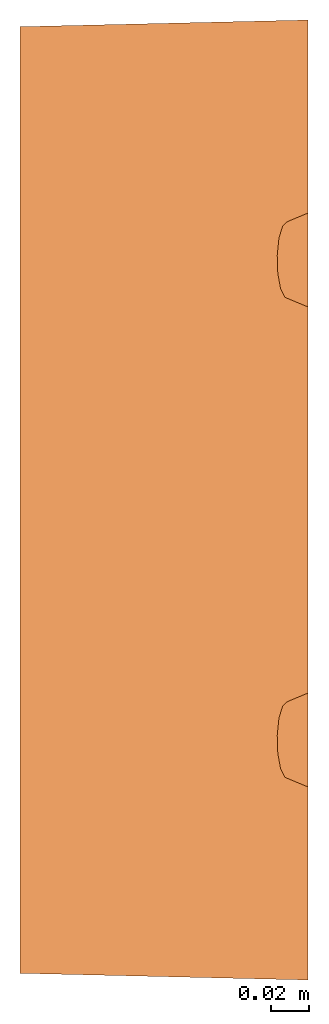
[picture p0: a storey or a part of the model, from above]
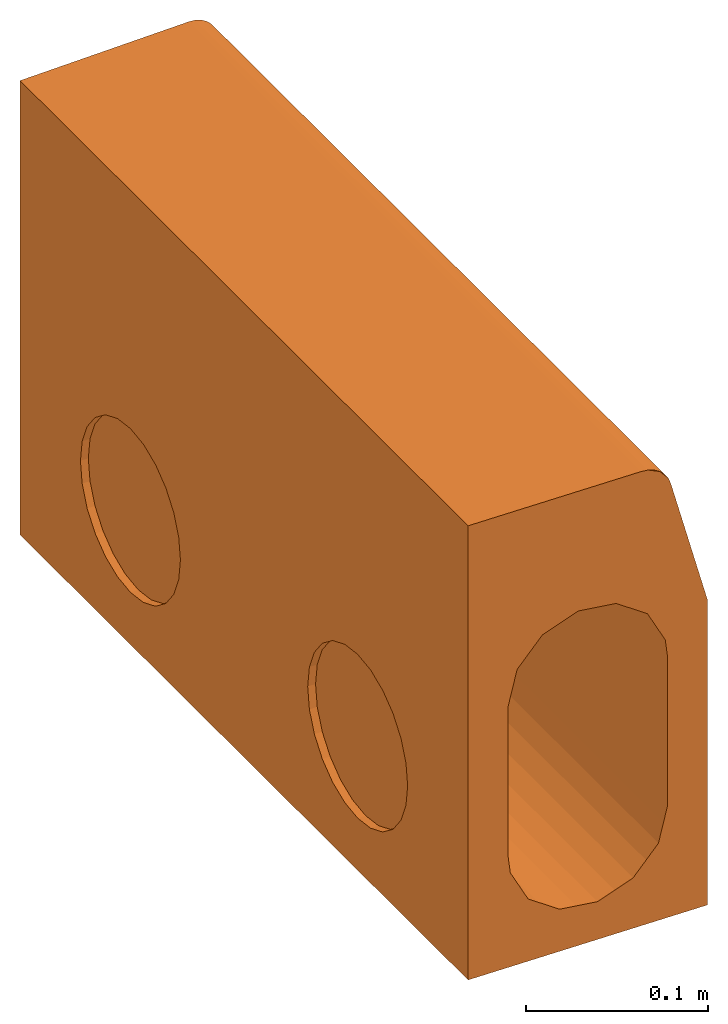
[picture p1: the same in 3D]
Properties of the parts of a building model (IFC2X3)

# File
Description: ViewDefinition [CoordinationView]
File name: 7970 - 25-11m external mitre.ifc
Time: 2013-09-12T12:57:16
Written by: Autodesk Revit 2013
Made in: 20120221_2030(x64)

# IfcProject, Project Number
LongName: Project Name; Phase: Project Status

# IfcSite, Default
RefLatitude: 42, 21, 30, 344238; RefLongitude: -71, -3, -35, -194702; RefElevation: 0 mm

# IfcBuilding
Pset_BuildingCommon - NumberOfStoreys: 2
Other - Client Name: Owner; Project Number: Project Number; Project Status: Project Status; Project Name: Project Name; Project Issue Date: Issue Date; Project Address: Enter address here

# IfcBuildingStorey (2)
Constraints - Elevation Base: 0
Graphics - Line Pattern: Center; Symbol at End 1 Default: no; Color: 0; Line Weight: 1; Symbol: M_Level Head - Circle: M_Level Head - Circle; Symbol at End 2 Default: yes
Identity Data - Structural: no; Building Story: yes
Dimensions - Computation Height: 0 mm
Name | LongName = Name | Elevation (mm) = Constraints, Elevation (mm)
T.O. Fnd. Wall | T.O. Fnd. Wall | -300
Level 1 | Level 1 | 0

# IfcBuildingElementProxy: 7970 - 25-11m external mitre, Civil-Drainage-Channel-ACO-KerbDrain-HB305 Part 2:7970 - 25-11m external mitre:7970 - 25-11m external mitre:263456
In: T.O. Fnd. Wall
Material: ACO Polymer Concrete.
Other - CreatedBy: www.aco.co.uk; Revision: 1
Dimensions - 1.8m Radius unit Void Start: -4800 mm; Curved LH Void End: 3010 mm; Quadrant void Start: 2600.7 mm; Straight Void Depth: -7500 mm; Quadrant void End: 2620.7 mm; Curved RH Void End: -3070 mm; Mitre Void End: -180 mm; 1.8m Radius Unit void End: -4805 mm; Flush Drainable Centre Stone Void Start: -4500 mm; Flush Drainable Centre Stone Void End: -4505 mm; 6m Radius unit void Start: -6000 mm; Void_Width: 150 mm; 6m Radius Unit Void end: -6005 mm; Mite Long Side Length: 497 mm; Void L Start: -3000 mm; Staright Void Depth: -7505 mm; Curved RH Void Start: -3060 mm; Void L End: -3010 mm; Curved LH Void Start: 3000 mm; mitre small length: 490 mm; Mitre Void Start: 0 mm; Void_Length: 500 mm; Volume: 12721656 mm3
Phasing - Phase Created: Phase 1
Constraints - Level: Level: Level 1; Moves With Nearby Elements: no
Pset_BuildingElementProxyCommon - Reference: 7970 - 25-11m external mitre
Identity Data - OmniClass Title: Rainwater Removal; Product brochure: http://www.aco.co.uk/download.php?id=120; Assembly Code: D2040; Product Page URL: http://www.aco.co.uk/product_detail.php?id=3; Manufacturer: ACO Technologies plc - ACO Water Management Division; URL: www.aco.co.uk; e-mail Technical: technical@aco.co.uk; Installation guidelines: http://www.aco.co.uk/download.php?id=120; Type Comments: ACO KerbDrain HB305 half battered 25-11m external mitre unit 500/493mm long; Model: ACO KerbDrain HB305; Fax: +44 (0)1462 815895; Model Description: Combined kerb and drainage system; e-mail Sales: customersupport@aco.co.uk; Product Code: 7970; Telephone: +44 (0)1462 816666; Price: POA - contact ACO; OmniClass Number: 23.70.50.24; Cost: 0; Address: ACO Business Park, Hitchin Road, Shefford, Bedfordshire, United Kingdom SG17 5TE; Maintenance guidelines: http://www.aco.co.uk/download.php?id=120; Assembly Description: Rain Water Drainage
Data - Hydraulic Performance: http://www.aco.co.uk/download.php?id=120; Connection Pipe O.D: N/A; Product Dimensions: 500/493mm x 150mm x 305mm (LxWxH); Installation - Concrete Grade: Refer to brochure; Concrete Surround Volume - Load Class A 15 - D 400 - Concrete Pavement: N/A; Drainage Slot Width: 50mm; Concrete Surround Volume - Load Class A 15 - D 400 - Grass or Asphalt Pavement: N/A; Channel C.S.A: 0.02m²; Drainage Slot Intake area: 14592mm²/m; Load Class: A 15 - D 400; Invert Depth: 280mm; Product Weight: 26.5 Kg; Product Standard: BS EN 1433:2002, CE marked, Kitemarked; ACO Hydraulic Design Software: http://www.acodesign.co.uk
General - TagNumber: 0.000000; SerialNumber: 0.000000
Materials and Finishes - Access Cover/Frame Colour: N/A; End Cap Colour: N/A; Connection Pipe Material: N/A; Access Cover/Frame Finish: N/A; Access Cover/Frame Material: N/A; End Cap Material: N/A; Connection Pipe Material Colour: N/A; Channel Colour: Grey; Channel Material: Vienite® Synthetic Resin Concrete
Green Building Properties - End Cap Recycled Material Content: N/A; Channel Recyclable: Fully recyclable; Access Cover/Frame Recycled Material Content: N/A; Access Cover/Frame Recyclable: N/A; End Cap Recyclable: N/A; Channel Recycled Material Content: 20% minimum
Construction - KDHB305 RH drop kerb-4999: no; KDHB305 6m _external_radius: no; KDHB305 internal_angle: no; KDHB305 1.8m_radius: no; flush drainable centre stone: no; KDHB305 10-8m_external_mitre: no; LH drop kerb- 6m ext rad: no; KDHB305 25-11m external_mitre: yes; KDHB305 25-11m internal_mitre: no; KDHB305 7-6m external_mitre: no; KDHB305_quadrant: no

# IfcOpeningElement: Recess (8)
In: Level 1
Constraints - Level: Level: Level 1; Related to Mass: no; Room Bounding: yes; Height Offset From Level: 0 mm
Structural - Structural: no; Enable Analytical Model: no
Dimensions - Area: 27858925 mm2; Thickness: 400 mm; Perimeter: 21157.2 mm; Volume: 11130245635 mm3
Phasing - Phase Created: Phase 1
Construction - Function: 0; Default Thickness: 400 mm
Analytical Properties - Absorptance: 0.1; Roughness: 1
Graphics - Coarse Scale Fill Color: 0

# IfcSlab: Floor:Generic Floor - 400mm, Floor:Generic Floor - 400mm:184025
In: Level 1
PredefinedType: FLOOR; Material: Default Floor 400 mm
Constraints - Level: Level: Level 1; Related to Mass: no; Room Bounding: yes; Height Offset From Level: 0 mm
Structural - Structural: no; Enable Analytical Model: no
Dimensions - Area: 27858925 mm2; Thickness: 400 mm; Perimeter: 21157.2 mm; Volume: 11130245635 mm3
Phasing - Phase Created: Phase 1
Pset_SlabCommon - Reference: Generic Floor - 400mm; IsExternal: no; LoadBearing: yes
Construction - Function: 0; Default Thickness: 400 mm
Analytical Properties - Absorptance: 0.1; Roughness: 1
Graphics - Coarse Scale Fill Color: 0
